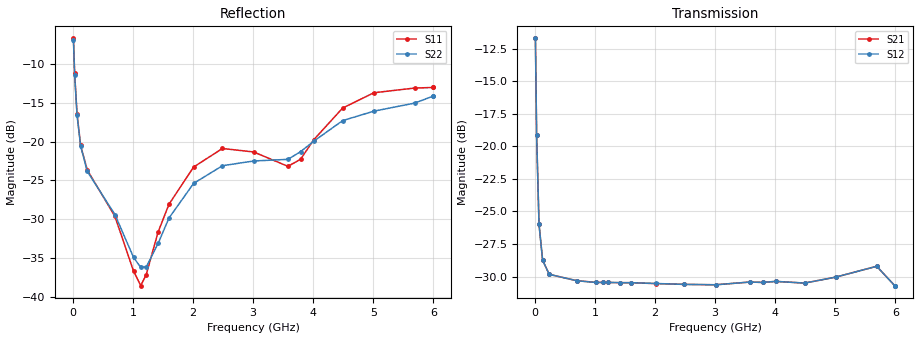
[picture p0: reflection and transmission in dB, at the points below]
! Integrated Device Technology
! Corporate Headquarters
! 6024 Silver Creek Valley Road
! San Jose, CA 95138  USA
! Phone:  1-408-284-8200
! Toll Free:  1-800-223-1366
! Webpage:  http://www.idt.com/
! Timing and RF Division
! 515 Groton Road, Suite 102
! Westford, MA 01886-6024
! Device:  F1951
! Description: 6-bit 0.5 dB Digital Step Attenuator
! Frequency:  100.0 -  4000.00 MHz
! Package:  4x4 mm Thin QFN Plastic Package: 24 pin
! Ports:  2 RF, 6 DC
!  Pin  1  = NC
!  Pin  2  = RF1  =  Port 1
!  Pin  3  = GND
!  Pin  4  = NC
!  Pin  5  = Serial Data Out (SDO)
!  Pin  6  = NC
!  Pin  7  = Reset Bar ( RSTb)
!  Pin  8  = Clock (CLK)
!  Pin  9  = Chip Select Bar (CSb)
!  Pin 10  = NC
!  Pin 11  = Serial Data In (SDI)
!  Pin 12  = NC
!  Pin 13  = NC
!  Pin 14  = VDD
!  Pin 15  = NC
!  Pin 16  = GND
!  Pin 17  = RF2  =  Port 2
!  Pin 18  = NC
!  Pin 19  = GND
!  Pin 20  = GND
!  Pin 21  = GND
!  Pin 22  = GND
!  Pin 23  = GND
!  Pin 24  = GND
! State:  59
! Atten State:  29.5 dB
! Voltage:  +3.30 Volts
! Current:  0.486 mA
! Data:  The device was measured on a F195X evaluation board which has
!  individual transmission lines to the RF pins.  Data was collected
!  de-embedded using a Automatic Fixture Removal [AFR] (Keysight Technologies).
!  The reference plane is the edge of the package pin.
! Misc:  Lot Code  1225BCA
!  Action Tracker AT0399
! Date Measured:  2018-09-13
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# GHz S dB R 50
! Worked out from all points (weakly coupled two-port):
!   600 points, 10 MHz to 6 GHz, reference 50 ohm
!   highest |S21| = -11.71 dB at 10 MHz (marker M1); lowest = -30.7 dB at 5.99 GHz (marker M2)
!   lowest |S11| = -38.6 dB at 1.13 GHz (marker M3), VSWR 1.02, Z = 48.9 + j0.238 ohm
!   |S11| at or under -10 dB: 23.88 MHz to end of sweep
!   |S22| runs from -36.6 to -6.9 dB; largest |S21 - S12| = 0.00014
!   S11 on the Smith chart (normalised r, x): 10 MHz: 1.73, -1.16; 30 MHz: 1.12, -0.59; 70 MHz: 0.97, -0.30; 1.22 GHz: 0.98, +0.02; 6 GHz: 0.81, +0.37
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0.01  -6.71 -34.9  -11.71 -43.6  -11.72 -43.6  -6.90 -35.2
0.03  -11.22 -62.7  -19.15 -64.0  -19.15 -64.1  -11.38 -62.2
0.07  -16.47 -87.3  -25.99 -52.8  -25.99 -52.8  -16.60 -87.1
0.13  -20.51 -106.1  -28.75 -35.4  -28.75 -35.4  -20.60 -105.6
0.24  -23.67 -122.8  -29.83 -22.3  -29.83 -22.2  -23.85 -122.4
0.7  -29.64 -136.3  -30.32 -14.1  -30.32 -14.1  -29.41 -138.2
1.01  -36.69 -158.2  -30.44 -15.0  -30.45 -15.0  -34.93 -153.5
1.13  -38.58 168.1  -30.45 -15.4  -30.45 -15.4  -36.23 -171.6
1.22  -37.18 141.3  -30.45 -15.9  -30.45 -15.9  -36.20 170.1
1.42  -31.64 117.3  -30.47 -17.3  -30.47 -17.3  -33.12 141.9
1.6  -28.09 114.6  -30.47 -18.6  -30.47 -18.6  -29.86 132.7
2.01  -23.29 122.6  -30.54 -22.1  -30.53 -22.1  -25.40 133.8
2.49  -20.90 135.4  -30.60 -26.1  -30.60 -26.0  -23.12 141.0
3.01  -21.35 145.3  -30.63 -30.0  -30.63 -30.0  -22.51 144.5
3.58  -23.20 123.9  -30.42 -34.4  -30.42 -34.4  -22.30 127.2
3.79  -22.29 108.2  -30.45 -36.1  -30.45 -36.1  -21.31 120.4
4.01  -19.77 100.0  -30.37 -37.9  -30.37 -37.9  -19.96 115.2
4.49  -15.69 98.5  -30.50 -41.2  -30.50 -41.2  -17.31 113.6
5.01  -13.72 107.3  -30.04 -42.3  -30.04 -42.3  -16.09 116.0
5.69  -13.11 112.4  -29.21 -53.9  -29.21 -53.9  -15.05 108.7
5.99  -13.04 106.3  -30.70 -55.0  -30.70 -55.0  -14.17 105.0
6  -13.04 106.0  -30.69 -54.3  -30.69 -54.3  -14.13 104.9
